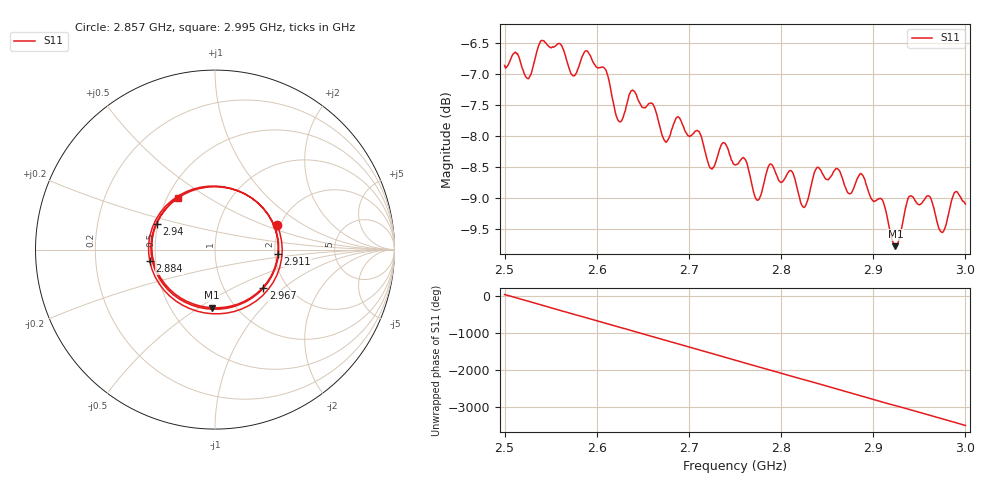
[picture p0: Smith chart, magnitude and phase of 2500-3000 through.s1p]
! NanoVNA-App by SYSJOINT et al v1.1.209 (+OD18)
! Date: 2025-09-17 10:38:50
! Start: 2.5GHz Stop: 3GHz Points: 501
! S-Parameter data: F S11
# Hz S RI R 50
!  Frequency  S11_Real  S11_Imag
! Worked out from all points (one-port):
!   501 points, 2.5 GHz to 3 GHz, reference 50 ohm
!   lowest |S11| = -9.8 dB at 2.924 GHz (marker M1), VSWR 1.96, Z = 39.2 - j28.3 ohm
!   |S11| at or under -10 dB: nowhere
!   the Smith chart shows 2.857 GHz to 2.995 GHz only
!   S11 on the Smith chart (normalised r, x): 2.857 GHz: 1.93, +0.61; 2.884 GHz: 0.46, -0.07; 2.911 GHz: 2.08, -0.11; 2.94 GHz: 0.49, +0.16; 2.967 GHz: 1.52, -0.74; 2.995 GHz: 0.57, +0.38
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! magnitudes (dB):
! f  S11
! 2.5 GHz  -6.9
! 2.563 GHz  -6.6
! 2.574 GHz  -7.0
! 2.588 GHz  -6.6
! 2.608 GHz  -6.9
! 2.625 GHz  -7.8
! 2.639 GHz  -7.3
! 2.674 GHz  -8.1
! 2.688 GHz  -7.7
! 2.724 GHz  -8.5
! 2.737 GHz  -8.1
! 2.75 GHz  -8.5
! 2.774 GHz  -9.0
! 2.788 GHz  -8.5
! 2.813 GHz  -8.6
! 2.825 GHz  -9.2
! 2.838 GHz  -8.5
! 2.857 GHz  -8.6
! 2.875 GHz  -8.9
! 2.884 GHz  -8.7
! 2.911 GHz  -9.1
! 2.924 GHz  -9.8
! 2.938 GHz  -9.0
! 2.94 GHz  -9.0
! 2.967 GHz  -9.3
! 2.975 GHz  -9.6
! 2.995 GHz  -9.0
! 3 GHz  -9.1
